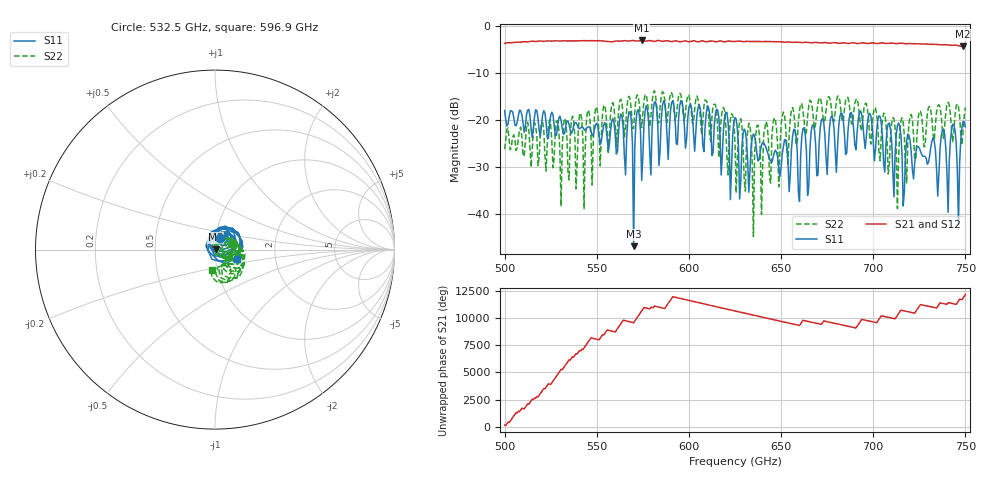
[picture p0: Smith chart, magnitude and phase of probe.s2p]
!Created with skrf (http://scikit-rf.org).
# GHz S RI R 50.0
!freq ReS11 ImS11 ReS21 ImS21 ReS12 ImS12 ReS22 ImS22
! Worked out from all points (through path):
!   401 points, 500 GHz to 750 GHz, reference 50 ohm
!   highest |S21| = -3.16 dB at 574.4 GHz (marker M1); lowest = -4.4 dB at 748.8 GHz (marker M2)
!   lowest |S11| = -46.8 dB at 570 GHz (marker M3), VSWR 1.01, Z = 50.4 + j0.145 ohm
!   |S11| at or under -10 dB: start of sweep to end of sweep
!   |S22| runs from -44.7 to -13.8 dB; largest |S21 - S12| = 6.2e-16
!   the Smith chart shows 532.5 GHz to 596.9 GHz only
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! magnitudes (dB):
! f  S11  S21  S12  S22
! 500 GHz  -18.0  -3.8  -3.8  -26.2
! 541.9 GHz  -21.6  -3.2  -3.2  -19.9
! 567.5 GHz  -18.3  -3.3  -3.3  -15.0
! 570 GHz  -46.8  -3.2  -3.2  -21.8
! 572.5 GHz  -17.8  -3.3  -3.3  -15.0
! 574.4 GHz  -32.9  -3.2  -3.2  -21.6
! 583.8 GHz  -29.7  -3.2  -3.2  -20.6
! 609.4 GHz  -18.7  -3.4  -3.4  -15.9
! 622.5 GHz  -36.9  -3.3  -3.3  -20.0
! 625 GHz  -19.5  -3.4  -3.4  -24.9
! 628.1 GHz  -33.0  -3.3  -3.3  -19.7
! 635 GHz  -23.0  -3.4  -3.4  -44.7
! 660 GHz  -37.3  -3.6  -3.6  -18.0
! 666.9 GHz  -21.2  -3.6  -3.6  -17.2
! 708.8 GHz  -20.7  -3.7  -3.7  -29.4
! 716.9 GHz  -35.3  -3.8  -3.8  -23.3
! 738.1 GHz  -21.9  -4.1  -4.1  -23.9
! 740.6 GHz  -39.6  -4.1  -4.1  -16.3
! 743.1 GHz  -20.9  -4.2  -4.2  -24.6
! 746.2 GHz  -42.2  -4.3  -4.3  -17.3
! 748.8 GHz  -20.3  -4.4  -4.4  -22.2
! 750 GHz  -21.5  -4.4  -4.4  -17.4
